VERSION 5.7 ;
NOWIREEXTENSIONATPIN ON ;
DIVIDERCHAR "/" ;
BUSBITCHARS "[]" ;

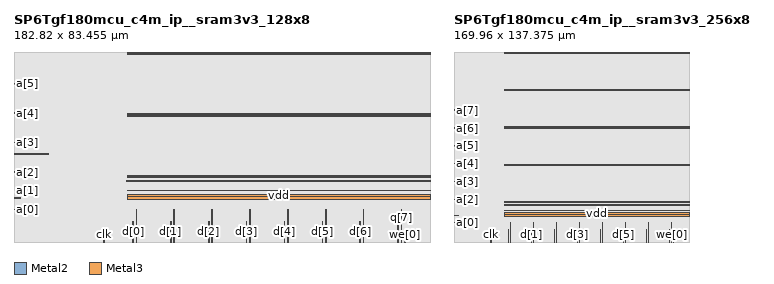
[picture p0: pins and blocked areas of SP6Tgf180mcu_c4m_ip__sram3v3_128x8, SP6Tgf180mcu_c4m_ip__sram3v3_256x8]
MACRO SP6Tgf180mcu_c4m_ip__sram3v3_128x8
  CLASS BLOCK ;
  FOREIGN SP6Tgf180mcu_c4m_ip__sram3v3_128x8 ;
  ORIGIN 0.000 0.000 ;
  SIZE 182.820 BY 83.455 ;
  SYMMETRY X Y R90 ;
  PIN clk
  USE CLOCK ;
  DIRECTION INPUT ;
  ANTENNAGATEAREA 0.492800 ;
  PORT
      LAYER Metal2 ;
      RECT 39.515 0.000 39.895 1.900 ;
  END
  END clk
  PIN a[0]
  USE SIGNAL ;
  DIRECTION INPUT ;
  ANTENNAGATEAREA 0.492800 ;
  PORT
      LAYER Metal3 ;
      RECT 0.000 14.065 2.980 14.345 ;
  END
  END a[0]
  PIN a[1]
  USE SIGNAL ;
  DIRECTION INPUT ;
  ANTENNAGATEAREA 0.492800 ;
  PORT
      LAYER Metal3 ;
      RECT 0.000 19.205 2.980 19.485 ;
  END
  END a[1]
  PIN a[2]
  USE SIGNAL ;
  DIRECTION INPUT ;
  ANTENNAGATEAREA 0.492800 ;
  PORT
      LAYER Metal3 ;
      RECT 0.000 30.605 2.510 30.885 ;
  END
  END a[2]
  PIN a[3]
  USE SIGNAL ;
  DIRECTION INPUT ;
  ANTENNAGATEAREA 0.492800 ;
  PORT
      LAYER Metal3 ;
      RECT 0.000 43.525 2.510 43.805 ;
  END
  END a[3]
  PIN a[4]
  USE SIGNAL ;
  DIRECTION INPUT ;
  ANTENNAGATEAREA 0.492800 ;
  PORT
      LAYER Metal3 ;
      RECT 0.000 56.445 2.510 56.725 ;
  END
  END a[4]
  PIN a[5]
  USE SIGNAL ;
  DIRECTION INPUT ;
  ANTENNAGATEAREA 0.492800 ;
  PORT
      LAYER Metal3 ;
      RECT 0.000 69.365 2.510 69.645 ;
  END
  END a[5]
  PIN a[6]
  USE SIGNAL ;
  DIRECTION INPUT ;
  ANTENNAGATEAREA 0.492800 ;
  PORT
      LAYER Metal3 ;
      RECT 0.000 38.385 15.010 38.665 ;
  END
  END a[6]
  PIN d[0]
  USE SIGNAL ;
  DIRECTION INPUT ;
  ANTENNAGATEAREA 0.492800 ;
  PORT
      LAYER Metal3 ;
      RECT 52.130 0.000 52.410 9.140 ;
  END
  END d[0]
  PIN d[1]
  USE SIGNAL ;
  DIRECTION INPUT ;
  ANTENNAGATEAREA 0.492800 ;
  PORT
      LAYER Metal3 ;
      RECT 68.770 0.000 69.050 9.140 ;
  END
  END d[1]
  PIN d[2]
  USE SIGNAL ;
  DIRECTION INPUT ;
  ANTENNAGATEAREA 0.492800 ;
  PORT
      LAYER Metal3 ;
      RECT 85.410 0.000 85.690 9.140 ;
  END
  END d[2]
  PIN d[3]
  USE SIGNAL ;
  DIRECTION INPUT ;
  ANTENNAGATEAREA 0.492800 ;
  PORT
      LAYER Metal3 ;
      RECT 102.050 0.000 102.330 9.140 ;
  END
  END d[3]
  PIN d[4]
  USE SIGNAL ;
  DIRECTION INPUT ;
  ANTENNAGATEAREA 0.492800 ;
  PORT
      LAYER Metal3 ;
      RECT 118.690 0.000 118.970 9.140 ;
  END
  END d[4]
  PIN d[5]
  USE SIGNAL ;
  DIRECTION INPUT ;
  ANTENNAGATEAREA 0.492800 ;
  PORT
      LAYER Metal3 ;
      RECT 135.330 0.000 135.610 9.140 ;
  END
  END d[5]
  PIN d[6]
  USE SIGNAL ;
  DIRECTION INPUT ;
  ANTENNAGATEAREA 0.492800 ;
  PORT
      LAYER Metal3 ;
      RECT 151.970 0.000 152.250 9.140 ;
  END
  END d[6]
  PIN d[7]
  USE SIGNAL ;
  DIRECTION INPUT ;
  ANTENNAGATEAREA 0.492800 ;
  PORT
      LAYER Metal3 ;
      RECT 168.610 0.000 168.890 9.140 ;
  END
  END d[7]
  PIN we[0]
  USE SIGNAL ;
  DIRECTION INPUT ;
  ANTENNAGATEAREA 0.492800 ;
  PORT
      LAYER Metal3 ;
      RECT 171.570 0.000 171.850 1.000 ;
  END
  END we[0]
  PIN q[0]
  USE SIGNAL ;
  DIRECTION OUTPUT ;
  PORT
      LAYER Metal3 ;
      RECT 53.590 0.000 53.870 14.190 ;
  END
  END q[0]
  PIN q[1]
  USE SIGNAL ;
  DIRECTION OUTPUT ;
  PORT
      LAYER Metal3 ;
      RECT 70.230 0.000 70.510 14.190 ;
  END
  END q[1]
  PIN q[2]
  USE SIGNAL ;
  DIRECTION OUTPUT ;
  PORT
      LAYER Metal3 ;
      RECT 86.870 0.000 87.150 14.190 ;
  END
  END q[2]
  PIN q[3]
  USE SIGNAL ;
  DIRECTION OUTPUT ;
  PORT
      LAYER Metal3 ;
      RECT 103.510 0.000 103.790 14.190 ;
  END
  END q[3]
  PIN q[4]
  USE SIGNAL ;
  DIRECTION OUTPUT ;
  PORT
      LAYER Metal3 ;
      RECT 120.150 0.000 120.430 14.190 ;
  END
  END q[4]
  PIN q[5]
  USE SIGNAL ;
  DIRECTION OUTPUT ;
  PORT
      LAYER Metal3 ;
      RECT 136.790 0.000 137.070 14.190 ;
  END
  END q[5]
  PIN q[6]
  USE SIGNAL ;
  DIRECTION OUTPUT ;
  PORT
      LAYER Metal3 ;
      RECT 153.430 0.000 153.710 14.190 ;
  END
  END q[6]
  PIN q[7]
  USE SIGNAL ;
  DIRECTION OUTPUT ;
  PORT
      LAYER Metal3 ;
      RECT 170.070 0.000 170.350 14.190 ;
  END
  END q[7]
  PIN vss
    USE GROUND ;
    DIRECTION INOUT ;
    PORT
      LAYER Metal3 ;
        RECT 49.700 18.780 182.820 19.780 ;
    END
    PORT
      LAYER Metal3 ;
        RECT 49.700 82.235 182.820 82.635 ;
    END
    PORT
      LAYER Metal3 ;
        RECT 49.700 55.275 182.820 55.675 ;
    END
    PORT
      LAYER Metal3 ;
        RECT 49.700 22.450 182.820 22.730 ;
    END
    PORT
      LAYER Metal3 ;
        RECT 49.700 28.315 182.820 28.715 ;
    END
  END vss
  PIN vdd
    USE POWER ;
    DIRECTION INOUT ;
    PORT
      LAYER Metal3 ;
        RECT 49.700 82.915 182.820 83.315 ;
    END
    PORT
      LAYER Metal3 ;
        RECT 49.700 28.995 182.820 29.395 ;
    END
    PORT
      LAYER Metal3 ;
        RECT 49.510 26.745 182.820 27.025 ;
    END
    PORT
      LAYER Metal3 ;
        RECT 49.700 55.955 182.820 56.355 ;
    END
    PORT
      LAYER Metal3 ;
        RECT 49.700 20.060 182.820 21.060 ;
    END
  END vdd
  OBS
    LAYER Metal1 ;
      RECT 0.000 0.000 182.820 83.455 ;
    LAYER Metal2 ;
      RECT 0.000 0.000 182.820 83.455 ;
    LAYER Metal3 ;
      RECT 0.000 0.000 182.820 83.455 ;
  END
END SP6Tgf180mcu_c4m_ip__sram3v3_128x8

MACRO SP6Tgf180mcu_c4m_ip__sram3v3_256x8
  CLASS BLOCK ;
  FOREIGN SP6Tgf180mcu_c4m_ip__sram3v3_256x8 ;
  ORIGIN 0.000 0.000 ;
  SIZE 169.960 BY 137.375 ;
  SYMMETRY X Y R90 ;
  PIN clk
  USE CLOCK ;
  DIRECTION INPUT ;
  ANTENNAGATEAREA 0.492800 ;
  PORT
      LAYER Metal2 ;
      RECT 26.655 0.000 27.035 1.900 ;
  END
  END clk
  PIN a[0]
  USE SIGNAL ;
  DIRECTION INPUT ;
  ANTENNAGATEAREA 0.492800 ;
  PORT
      LAYER Metal3 ;
      RECT 0.000 14.065 2.980 14.345 ;
  END
  END a[0]
  PIN a[1]
  USE SIGNAL ;
  DIRECTION INPUT ;
  ANTENNAGATEAREA 0.492800 ;
  PORT
      LAYER Metal3 ;
      RECT 0.000 19.205 2.980 19.485 ;
  END
  END a[1]
  PIN a[2]
  USE SIGNAL ;
  DIRECTION INPUT ;
  ANTENNAGATEAREA 0.492800 ;
  PORT
      LAYER Metal3 ;
      RECT 0.000 30.605 2.510 30.885 ;
  END
  END a[2]
  PIN a[3]
  USE SIGNAL ;
  DIRECTION INPUT ;
  ANTENNAGATEAREA 0.492800 ;
  PORT
      LAYER Metal3 ;
      RECT 0.000 43.525 2.510 43.805 ;
  END
  END a[3]
  PIN a[4]
  USE SIGNAL ;
  DIRECTION INPUT ;
  ANTENNAGATEAREA 0.492800 ;
  PORT
      LAYER Metal3 ;
      RECT 0.000 56.445 2.510 56.725 ;
  END
  END a[4]
  PIN a[5]
  USE SIGNAL ;
  DIRECTION INPUT ;
  ANTENNAGATEAREA 0.492800 ;
  PORT
      LAYER Metal3 ;
      RECT 0.000 69.365 2.510 69.645 ;
  END
  END a[5]
  PIN a[6]
  USE SIGNAL ;
  DIRECTION INPUT ;
  ANTENNAGATEAREA 0.492800 ;
  PORT
      LAYER Metal3 ;
      RECT 0.000 82.285 2.510 82.565 ;
  END
  END a[6]
  PIN a[7]
  USE SIGNAL ;
  DIRECTION INPUT ;
  ANTENNAGATEAREA 0.492800 ;
  PORT
      LAYER Metal3 ;
      RECT 0.000 95.205 2.510 95.485 ;
  END
  END a[7]
  PIN d[0]
  USE SIGNAL ;
  DIRECTION INPUT ;
  ANTENNAGATEAREA 0.492800 ;
  PORT
      LAYER Metal3 ;
      RECT 39.270 0.000 39.550 9.140 ;
  END
  END d[0]
  PIN d[1]
  USE SIGNAL ;
  DIRECTION INPUT ;
  ANTENNAGATEAREA 0.492800 ;
  PORT
      LAYER Metal3 ;
      RECT 55.910 0.000 56.190 9.140 ;
  END
  END d[1]
  PIN d[2]
  USE SIGNAL ;
  DIRECTION INPUT ;
  ANTENNAGATEAREA 0.492800 ;
  PORT
      LAYER Metal3 ;
      RECT 72.550 0.000 72.830 9.140 ;
  END
  END d[2]
  PIN d[3]
  USE SIGNAL ;
  DIRECTION INPUT ;
  ANTENNAGATEAREA 0.492800 ;
  PORT
      LAYER Metal3 ;
      RECT 89.190 0.000 89.470 9.140 ;
  END
  END d[3]
  PIN d[4]
  USE SIGNAL ;
  DIRECTION INPUT ;
  ANTENNAGATEAREA 0.492800 ;
  PORT
      LAYER Metal3 ;
      RECT 105.830 0.000 106.110 9.140 ;
  END
  END d[4]
  PIN d[5]
  USE SIGNAL ;
  DIRECTION INPUT ;
  ANTENNAGATEAREA 0.492800 ;
  PORT
      LAYER Metal3 ;
      RECT 122.470 0.000 122.750 9.140 ;
  END
  END d[5]
  PIN d[6]
  USE SIGNAL ;
  DIRECTION INPUT ;
  ANTENNAGATEAREA 0.492800 ;
  PORT
      LAYER Metal3 ;
      RECT 139.110 0.000 139.390 9.140 ;
  END
  END d[6]
  PIN d[7]
  USE SIGNAL ;
  DIRECTION INPUT ;
  ANTENNAGATEAREA 0.492800 ;
  PORT
      LAYER Metal3 ;
      RECT 155.750 0.000 156.030 9.140 ;
  END
  END d[7]
  PIN we[0]
  USE SIGNAL ;
  DIRECTION INPUT ;
  ANTENNAGATEAREA 0.492800 ;
  PORT
      LAYER Metal3 ;
      RECT 158.710 0.000 158.990 1.000 ;
  END
  END we[0]
  PIN q[0]
  USE SIGNAL ;
  DIRECTION OUTPUT ;
  PORT
      LAYER Metal3 ;
      RECT 40.730 0.000 41.010 14.190 ;
  END
  END q[0]
  PIN q[1]
  USE SIGNAL ;
  DIRECTION OUTPUT ;
  PORT
      LAYER Metal3 ;
      RECT 57.370 0.000 57.650 14.190 ;
  END
  END q[1]
  PIN q[2]
  USE SIGNAL ;
  DIRECTION OUTPUT ;
  PORT
      LAYER Metal3 ;
      RECT 74.010 0.000 74.290 14.190 ;
  END
  END q[2]
  PIN q[3]
  USE SIGNAL ;
  DIRECTION OUTPUT ;
  PORT
      LAYER Metal3 ;
      RECT 90.650 0.000 90.930 14.190 ;
  END
  END q[3]
  PIN q[4]
  USE SIGNAL ;
  DIRECTION OUTPUT ;
  PORT
      LAYER Metal3 ;
      RECT 107.290 0.000 107.570 14.190 ;
  END
  END q[4]
  PIN q[5]
  USE SIGNAL ;
  DIRECTION OUTPUT ;
  PORT
      LAYER Metal3 ;
      RECT 123.930 0.000 124.210 14.190 ;
  END
  END q[5]
  PIN q[6]
  USE SIGNAL ;
  DIRECTION OUTPUT ;
  PORT
      LAYER Metal3 ;
      RECT 140.570 0.000 140.850 14.190 ;
  END
  END q[6]
  PIN q[7]
  USE SIGNAL ;
  DIRECTION OUTPUT ;
  PORT
      LAYER Metal3 ;
      RECT 157.210 0.000 157.490 14.190 ;
  END
  END q[7]
  PIN vss
    USE GROUND ;
    DIRECTION INOUT ;
    PORT
      LAYER Metal3 ;
        RECT 36.840 55.275 169.960 55.675 ;
    END
    PORT
      LAYER Metal3 ;
        RECT 36.840 82.235 169.960 82.635 ;
    END
    PORT
      LAYER Metal3 ;
        RECT 36.840 18.780 169.960 19.780 ;
    END
    PORT
      LAYER Metal3 ;
        RECT 36.840 28.315 169.960 28.715 ;
    END
    PORT
      LAYER Metal3 ;
        RECT 36.840 136.155 169.960 136.555 ;
    END
    PORT
      LAYER Metal3 ;
        RECT 36.840 109.195 169.960 109.595 ;
    END
    PORT
      LAYER Metal3 ;
        RECT 36.840 22.450 169.960 22.730 ;
    END
  END vss
  PIN vdd
    USE POWER ;
    DIRECTION INOUT ;
    PORT
      LAYER Metal3 ;
        RECT 36.840 28.995 169.960 29.395 ;
    END
    PORT
      LAYER Metal3 ;
        RECT 36.840 55.955 169.960 56.355 ;
    END
    PORT
      LAYER Metal3 ;
        RECT 36.840 136.835 169.960 137.235 ;
    END
    PORT
      LAYER Metal3 ;
        RECT 36.840 82.915 169.960 83.315 ;
    END
    PORT
      LAYER Metal3 ;
        RECT 36.840 20.060 169.960 21.060 ;
    END
    PORT
      LAYER Metal3 ;
        RECT 36.840 109.875 169.960 110.275 ;
    END
    PORT
      LAYER Metal3 ;
        RECT 36.650 26.745 169.960 27.025 ;
    END
  END vdd
  OBS
    LAYER Metal1 ;
      RECT 0.000 0.000 169.960 137.375 ;
    LAYER Metal2 ;
      RECT 0.000 0.000 169.960 137.375 ;
    LAYER Metal3 ;
      RECT 0.000 0.000 169.960 137.375 ;
  END
END SP6Tgf180mcu_c4m_ip__sram3v3_256x8

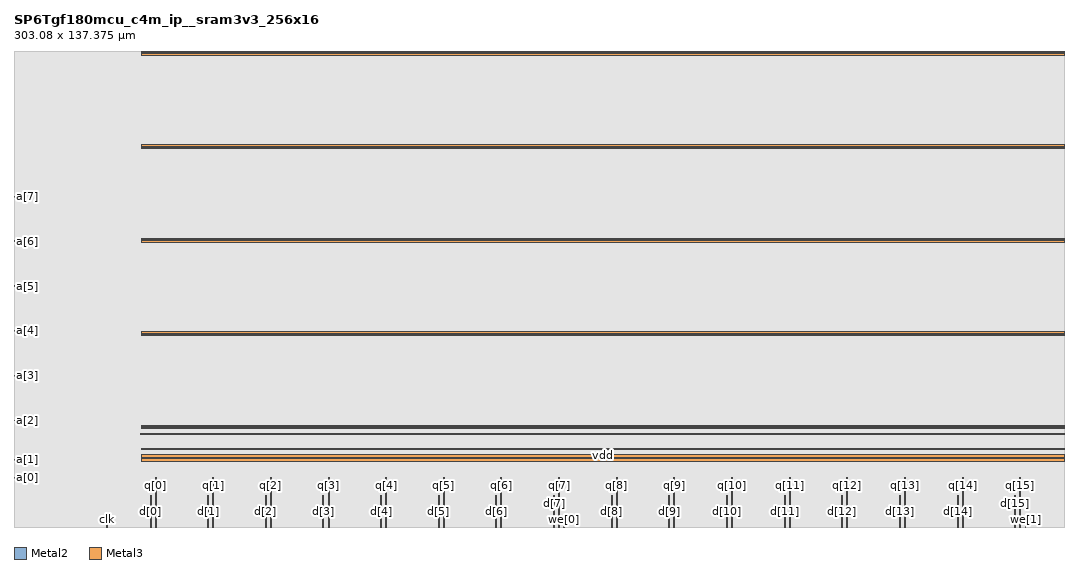
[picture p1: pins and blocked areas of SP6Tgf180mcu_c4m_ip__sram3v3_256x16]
MACRO SP6Tgf180mcu_c4m_ip__sram3v3_256x16
  CLASS BLOCK ;
  FOREIGN SP6Tgf180mcu_c4m_ip__sram3v3_256x16 ;
  ORIGIN 0.000 0.000 ;
  SIZE 303.080 BY 137.375 ;
  SYMMETRY X Y R90 ;
  PIN clk
  USE CLOCK ;
  DIRECTION INPUT ;
  ANTENNAGATEAREA 0.492800 ;
  PORT
      LAYER Metal2 ;
      RECT 26.655 0.000 27.035 1.900 ;
  END
  END clk
  PIN a[0]
  USE SIGNAL ;
  DIRECTION INPUT ;
  ANTENNAGATEAREA 0.492800 ;
  PORT
      LAYER Metal3 ;
      RECT 0.000 14.065 2.980 14.345 ;
  END
  END a[0]
  PIN a[1]
  USE SIGNAL ;
  DIRECTION INPUT ;
  ANTENNAGATEAREA 0.492800 ;
  PORT
      LAYER Metal3 ;
      RECT 0.000 19.205 2.980 19.485 ;
  END
  END a[1]
  PIN a[2]
  USE SIGNAL ;
  DIRECTION INPUT ;
  ANTENNAGATEAREA 0.492800 ;
  PORT
      LAYER Metal3 ;
      RECT 0.000 30.605 2.510 30.885 ;
  END
  END a[2]
  PIN a[3]
  USE SIGNAL ;
  DIRECTION INPUT ;
  ANTENNAGATEAREA 0.492800 ;
  PORT
      LAYER Metal3 ;
      RECT 0.000 43.525 2.510 43.805 ;
  END
  END a[3]
  PIN a[4]
  USE SIGNAL ;
  DIRECTION INPUT ;
  ANTENNAGATEAREA 0.492800 ;
  PORT
      LAYER Metal3 ;
      RECT 0.000 56.445 2.510 56.725 ;
  END
  END a[4]
  PIN a[5]
  USE SIGNAL ;
  DIRECTION INPUT ;
  ANTENNAGATEAREA 0.492800 ;
  PORT
      LAYER Metal3 ;
      RECT 0.000 69.365 2.510 69.645 ;
  END
  END a[5]
  PIN a[6]
  USE SIGNAL ;
  DIRECTION INPUT ;
  ANTENNAGATEAREA 0.492800 ;
  PORT
      LAYER Metal3 ;
      RECT 0.000 82.285 2.510 82.565 ;
  END
  END a[6]
  PIN a[7]
  USE SIGNAL ;
  DIRECTION INPUT ;
  ANTENNAGATEAREA 0.492800 ;
  PORT
      LAYER Metal3 ;
      RECT 0.000 95.205 2.510 95.485 ;
  END
  END a[7]
  PIN d[0]
  USE SIGNAL ;
  DIRECTION INPUT ;
  ANTENNAGATEAREA 0.492800 ;
  PORT
      LAYER Metal3 ;
      RECT 39.270 0.000 39.550 9.140 ;
  END
  END d[0]
  PIN d[1]
  USE SIGNAL ;
  DIRECTION INPUT ;
  ANTENNAGATEAREA 0.492800 ;
  PORT
      LAYER Metal3 ;
      RECT 55.910 0.000 56.190 9.140 ;
  END
  END d[1]
  PIN d[2]
  USE SIGNAL ;
  DIRECTION INPUT ;
  ANTENNAGATEAREA 0.492800 ;
  PORT
      LAYER Metal3 ;
      RECT 72.550 0.000 72.830 9.140 ;
  END
  END d[2]
  PIN d[3]
  USE SIGNAL ;
  DIRECTION INPUT ;
  ANTENNAGATEAREA 0.492800 ;
  PORT
      LAYER Metal3 ;
      RECT 89.190 0.000 89.470 9.140 ;
  END
  END d[3]
  PIN d[4]
  USE SIGNAL ;
  DIRECTION INPUT ;
  ANTENNAGATEAREA 0.492800 ;
  PORT
      LAYER Metal3 ;
      RECT 105.830 0.000 106.110 9.140 ;
  END
  END d[4]
  PIN d[5]
  USE SIGNAL ;
  DIRECTION INPUT ;
  ANTENNAGATEAREA 0.492800 ;
  PORT
      LAYER Metal3 ;
      RECT 122.470 0.000 122.750 9.140 ;
  END
  END d[5]
  PIN d[6]
  USE SIGNAL ;
  DIRECTION INPUT ;
  ANTENNAGATEAREA 0.492800 ;
  PORT
      LAYER Metal3 ;
      RECT 139.110 0.000 139.390 9.140 ;
  END
  END d[6]
  PIN d[7]
  USE SIGNAL ;
  DIRECTION INPUT ;
  ANTENNAGATEAREA 0.492800 ;
  PORT
      LAYER Metal3 ;
      RECT 155.750 0.000 156.030 9.140 ;
  END
  END d[7]
  PIN d[8]
  USE SIGNAL ;
  DIRECTION INPUT ;
  ANTENNAGATEAREA 0.492800 ;
  PORT
      LAYER Metal3 ;
      RECT 172.390 0.000 172.670 9.140 ;
  END
  END d[8]
  PIN d[9]
  USE SIGNAL ;
  DIRECTION INPUT ;
  ANTENNAGATEAREA 0.492800 ;
  PORT
      LAYER Metal3 ;
      RECT 189.030 0.000 189.310 9.140 ;
  END
  END d[9]
  PIN d[10]
  USE SIGNAL ;
  DIRECTION INPUT ;
  ANTENNAGATEAREA 0.492800 ;
  PORT
      LAYER Metal3 ;
      RECT 205.670 0.000 205.950 9.140 ;
  END
  END d[10]
  PIN d[11]
  USE SIGNAL ;
  DIRECTION INPUT ;
  ANTENNAGATEAREA 0.492800 ;
  PORT
      LAYER Metal3 ;
      RECT 222.310 0.000 222.590 9.140 ;
  END
  END d[11]
  PIN d[12]
  USE SIGNAL ;
  DIRECTION INPUT ;
  ANTENNAGATEAREA 0.492800 ;
  PORT
      LAYER Metal3 ;
      RECT 238.950 0.000 239.230 9.140 ;
  END
  END d[12]
  PIN d[13]
  USE SIGNAL ;
  DIRECTION INPUT ;
  ANTENNAGATEAREA 0.492800 ;
  PORT
      LAYER Metal3 ;
      RECT 255.590 0.000 255.870 9.140 ;
  END
  END d[13]
  PIN d[14]
  USE SIGNAL ;
  DIRECTION INPUT ;
  ANTENNAGATEAREA 0.492800 ;
  PORT
      LAYER Metal3 ;
      RECT 272.230 0.000 272.510 9.140 ;
  END
  END d[14]
  PIN d[15]
  USE SIGNAL ;
  DIRECTION INPUT ;
  ANTENNAGATEAREA 0.492800 ;
  PORT
      LAYER Metal3 ;
      RECT 288.870 0.000 289.150 9.140 ;
  END
  END d[15]
  PIN we[0]
  USE SIGNAL ;
  DIRECTION INPUT ;
  ANTENNAGATEAREA 0.492800 ;
  PORT
      LAYER Metal3 ;
      RECT 158.710 0.000 158.990 1.000 ;
  END
  END we[0]
  PIN we[1]
  USE SIGNAL ;
  DIRECTION INPUT ;
  ANTENNAGATEAREA 0.492800 ;
  PORT
      LAYER Metal3 ;
      RECT 291.830 0.000 292.110 1.000 ;
  END
  END we[1]
  PIN q[0]
  USE SIGNAL ;
  DIRECTION OUTPUT ;
  PORT
      LAYER Metal3 ;
      RECT 40.730 0.000 41.010 14.190 ;
  END
  END q[0]
  PIN q[1]
  USE SIGNAL ;
  DIRECTION OUTPUT ;
  PORT
      LAYER Metal3 ;
      RECT 57.370 0.000 57.650 14.190 ;
  END
  END q[1]
  PIN q[2]
  USE SIGNAL ;
  DIRECTION OUTPUT ;
  PORT
      LAYER Metal3 ;
      RECT 74.010 0.000 74.290 14.190 ;
  END
  END q[2]
  PIN q[3]
  USE SIGNAL ;
  DIRECTION OUTPUT ;
  PORT
      LAYER Metal3 ;
      RECT 90.650 0.000 90.930 14.190 ;
  END
  END q[3]
  PIN q[4]
  USE SIGNAL ;
  DIRECTION OUTPUT ;
  PORT
      LAYER Metal3 ;
      RECT 107.290 0.000 107.570 14.190 ;
  END
  END q[4]
  PIN q[5]
  USE SIGNAL ;
  DIRECTION OUTPUT ;
  PORT
      LAYER Metal3 ;
      RECT 123.930 0.000 124.210 14.190 ;
  END
  END q[5]
  PIN q[6]
  USE SIGNAL ;
  DIRECTION OUTPUT ;
  PORT
      LAYER Metal3 ;
      RECT 140.570 0.000 140.850 14.190 ;
  END
  END q[6]
  PIN q[7]
  USE SIGNAL ;
  DIRECTION OUTPUT ;
  PORT
      LAYER Metal3 ;
      RECT 157.210 0.000 157.490 14.190 ;
  END
  END q[7]
  PIN q[8]
  USE SIGNAL ;
  DIRECTION OUTPUT ;
  PORT
      LAYER Metal3 ;
      RECT 173.850 0.000 174.130 14.190 ;
  END
  END q[8]
  PIN q[9]
  USE SIGNAL ;
  DIRECTION OUTPUT ;
  PORT
      LAYER Metal3 ;
      RECT 190.490 0.000 190.770 14.190 ;
  END
  END q[9]
  PIN q[10]
  USE SIGNAL ;
  DIRECTION OUTPUT ;
  PORT
      LAYER Metal3 ;
      RECT 207.130 0.000 207.410 14.190 ;
  END
  END q[10]
  PIN q[11]
  USE SIGNAL ;
  DIRECTION OUTPUT ;
  PORT
      LAYER Metal3 ;
      RECT 223.770 0.000 224.050 14.190 ;
  END
  END q[11]
  PIN q[12]
  USE SIGNAL ;
  DIRECTION OUTPUT ;
  PORT
      LAYER Metal3 ;
      RECT 240.410 0.000 240.690 14.190 ;
  END
  END q[12]
  PIN q[13]
  USE SIGNAL ;
  DIRECTION OUTPUT ;
  PORT
      LAYER Metal3 ;
      RECT 257.050 0.000 257.330 14.190 ;
  END
  END q[13]
  PIN q[14]
  USE SIGNAL ;
  DIRECTION OUTPUT ;
  PORT
      LAYER Metal3 ;
      RECT 273.690 0.000 273.970 14.190 ;
  END
  END q[14]
  PIN q[15]
  USE SIGNAL ;
  DIRECTION OUTPUT ;
  PORT
      LAYER Metal3 ;
      RECT 290.330 0.000 290.610 14.190 ;
  END
  END q[15]
  PIN vss
    USE GROUND ;
    DIRECTION INOUT ;
    PORT
      LAYER Metal3 ;
        RECT 36.840 28.315 303.080 28.715 ;
    END
    PORT
      LAYER Metal3 ;
        RECT 36.840 22.450 303.080 22.730 ;
    END
    PORT
      LAYER Metal3 ;
        RECT 36.840 82.235 303.080 82.635 ;
    END
    PORT
      LAYER Metal3 ;
        RECT 36.840 55.275 303.080 55.675 ;
    END
    PORT
      LAYER Metal3 ;
        RECT 36.840 136.155 303.080 136.555 ;
    END
    PORT
      LAYER Metal3 ;
        RECT 36.840 109.195 303.080 109.595 ;
    END
    PORT
      LAYER Metal3 ;
        RECT 36.840 18.780 303.080 19.780 ;
    END
  END vss
  PIN vdd
    USE POWER ;
    DIRECTION INOUT ;
    PORT
      LAYER Metal3 ;
        RECT 36.840 55.955 303.080 56.355 ;
    END
    PORT
      LAYER Metal3 ;
        RECT 36.840 20.060 303.080 21.060 ;
    END
    PORT
      LAYER Metal3 ;
        RECT 36.840 109.875 303.080 110.275 ;
    END
    PORT
      LAYER Metal3 ;
        RECT 36.840 82.915 303.080 83.315 ;
    END
    PORT
      LAYER Metal3 ;
        RECT 36.840 28.995 303.080 29.395 ;
    END
    PORT
      LAYER Metal3 ;
        RECT 36.840 136.835 303.080 137.235 ;
    END
    PORT
      LAYER Metal3 ;
        RECT 36.650 26.745 303.080 27.025 ;
    END
  END vdd
  OBS
    LAYER Metal1 ;
      RECT 0.000 0.000 303.080 137.375 ;
    LAYER Metal2 ;
      RECT 0.000 0.000 303.080 137.375 ;
    LAYER Metal3 ;
      RECT 0.000 0.000 303.080 137.375 ;
  END
END SP6Tgf180mcu_c4m_ip__sram3v3_256x16
